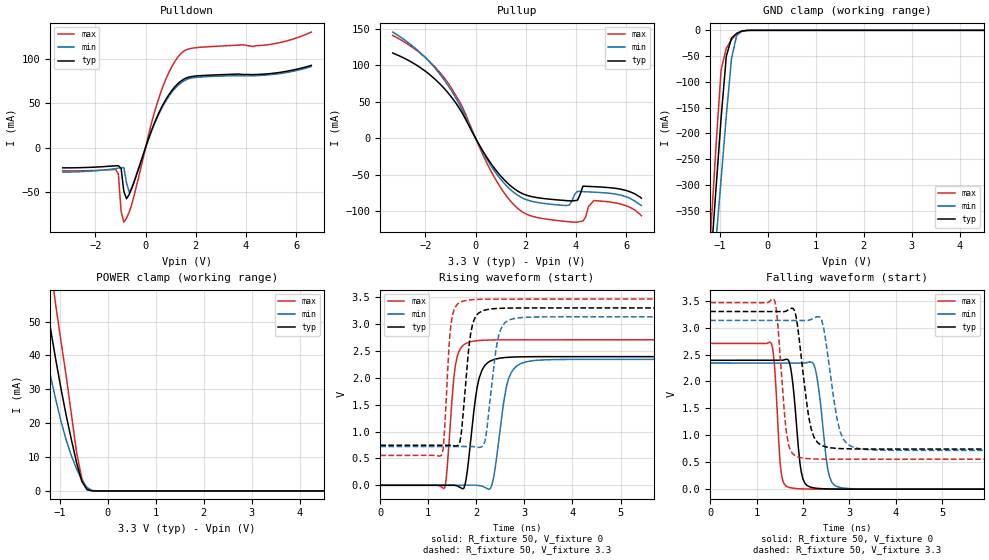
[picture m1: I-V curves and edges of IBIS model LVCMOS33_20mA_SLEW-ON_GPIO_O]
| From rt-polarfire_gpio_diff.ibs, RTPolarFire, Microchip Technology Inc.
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|   Model LVCMOS33_20mA_SLEW-ON_GPIO_O
[Model]   LVCMOS33_20mA_SLEW-ON_GPIO_O
Model_type   Output
Polarity   Non-Inverting
Enable   Active-High
Vmeas =   1.65
Cref =   5p
Rref =   1M
|   typ   min   max
C_comp_pullup   2.605e-12   2.605e-12   2.76e-12
C_comp_pulldown  2.605e-12   2.605e-12   2.76e-12
[Temperature Range]  25C   125C   -55C
[Voltage Range]  3.3   3.135   3.465
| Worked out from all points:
|   slope of the pulldown table from 0 to 0.495 V, typ, clamps not added: 13.4 ohm
|   slope of the pullup table from 0 to 0.495 V, typ, clamps not added: 17.3 ohm
|   GND clamp passes 1 mA (typ) near -0.51 V on its own axis
|   POWER clamp passes 1 mA (typ) near -0.46 V on its own axis
|   rising waveform, R_fixture 50, V_fixture 0: 20-80 % time 199ps typ, 224ps min, 143ps max; typ from 0 V to 2.39 V
|   rising waveform, R_fixture 50, V_fixture 3.3: 20-80 % time 160ps typ, 194ps min, 115ps max; typ from 0.745 V to 3.3 V
|   falling waveform, R_fixture 50, V_fixture 0: 20-80 % time 149ps typ, 181ps min, 107ps max; typ from 2.39 V to 0 V
|   falling waveform, R_fixture 50, V_fixture 3.3: 20-80 % time 226ps typ, 254ps min, 158ps max; typ from 3.3 V to 0.745 V
[GND Clamp]
| Voltage   I(typ)   I(min)   I(max)
-3.3V     -3.213A    -2.953A    -3.676A
-1.191V   -450mA     -534.3mA   -393.2mA
-1.083V   -310.2mA   -411.6mA   -227.5mA
-974.5mV  -170.4mA   -288.9mA   -76.97mA
-866.2mV  -50.48mA   -166.3mA   -34.78mA
-758mV    -15.08mA   -54.7mA    -18.33mA
-649.7mV  -5.883mA   -9.683mA   -6.874mA
-541.4mV  -1.389mA   -1.864mA   -1.426mA
-324.8mV  -3.553uA   -16.68uA   -1.172uA
6.6V      0A         0A         0A
[POWER Clamp]
| Voltage   I(typ)   I(min)   I(max)
-3.3V     320.3mA    256.6mA    387.1mA
-1.624V   89.11mA    65.97mA    116.9mA
-1.408V   67.23mA    48.87mA    90.32mA
-1.299V   57.08mA    41.04mA    77.84mA
-1.191V   47.51mA    33.68mA    65.79mA
-1.083V   38.51mA    26.79mA    54.52mA
-866.2mV  22.14mA    14.9mA     33.75mA
-649.7mV  8.213mA    6.429mA    11.19mA
-541.4mV  2.791mA    3.18mA     3.642mA
-433.1mV  359.8uA    981.3uA    499.4uA
-216.6mV  159.8nA    8.88uA     59.07nA
6.6V      0A         0A         0A
[Pullup]
| Voltage   I(typ)   I(min)   I(max)
-3.3V     117mA      145.7mA    141.1mA
-2.057V   93.5mA     112.8mA    112.5mA
-1.191V   66.14mA    77.19mA    80.37mA
-541.4mV  35.17mA    39.57mA    43.91mA
618.8mV   -34.87mA   -38.07mA   -45.43mA
1.753V    -73.94mA   -79.81mA   -98.31mA
3.625V    -85.57mA   -92.33mA   -114.2mA
4.058V    -84.98mA   -72.83mA   -114.9mA
4.275V    -65.71mA   -73.19mA   -113.6mA
4.708V    -66.38mA   -73.95mA   -85.52mA
5.79V     -69.97mA   -78.11mA   -90.3mA
6.6V      -82.26mA   -92.3mA    -106.2mA
[Pulldown]
| Voltage   I(typ)   I(min)   I(max)
-3.3V     -22.95mA   -27.7mA    -26.21mA
-1.191V   -20.65mA   -23.8mA    -24.73mA
-1.083V   -20.45mA   -23.29mA   -29.63mA
-974.5mV  -23.56mA   -22.74mA   -72.15mA
-866.2mV  -49.58mA   -22.71mA   -84.24mA
-758mV    -57.79mA   -39.9mA    -79.68mA
-649.7mV  -52.66mA   -50.34mA   -72.76mA
515.6mV   38.32mA    37.03mA    54.75mA
928.1mV   59.63mA    57.85mA    84.81mA
1.444V    75.7mA     73.69mA    107mA
4.924V    83.32mA    82.08mA    116.2mA
6.6V      92.71mA    91.43mA    130.3mA
[Ramp]
dV/dt_r   1.43641/0.199051n  1.40571/0.224051n  1.62438/0.143217n
dV/dt_f   1.53328/0.226109n  1.44881/0.253893n  1.74553/0.158052n
R_load = 50
[Rising Waveform]
R_fixture = 50
V_fixture = 0
V_fixture_min = 0
V_fixture_max = 0
| Time   V(typ)   V(min)   V(max)
0s        32.7nV     45.65nV    84.14nV
1.332ns   814.5uV    553.9uV    -55.06mV
1.563ns   -3.648mV   649.9uV    2.226V
1.741ns   -50.85mV   724uV      2.616V
1.863ns   674.6mV    774.7uV    2.668V
2.115ns   2.141V     -16.32mV   2.698V
2.324ns   2.326V     9.939mV    2.704V
2.666ns   2.381V     1.972V     2.707V
3.008ns   2.391V     2.291V     2.707V
10ns      2.394V     2.343V     2.707V
[Rising Waveform]
R_fixture = 50
V_fixture = 3.3
V_fixture_min = 3.135
V_fixture_max = 3.465
| Time   V(typ)   V(min)   V(max)
0s        744.5mV    720.3mV    555.8mV
1.283ns   745.3mV    721mV      574.7mV
1.468ns   745.2mV    721.1mV    2.966V
1.642ns   771mV      721.2mV    3.394V
1.717ns   1.259V     721.2mV    3.425V
1.944ns   3.059V     719.5mV    3.455V
2.182ns   3.261V     830.6mV    3.463V
2.439ns   3.29V      2.684V     3.464V
2.695ns   3.297V     3.08V      3.464V
10ns      3.3V       3.135V     3.465V
[Falling Waveform]
R_fixture = 50
V_fixture = 0
V_fixture_min = 0
V_fixture_max = 0
| Time   V(typ)   V(min)   V(max)
0s        2.394V     2.343V     2.707V
1.307ns   2.395V     2.342V     2.718V
1.528ns   2.395V     2.342V     315.6mV
1.706ns   2.349V     2.342V     30.97mV
1.961ns   321.5mV    2.342V     6.279mV
2.146ns   41.12mV    2.362V     2.346mV
2.301ns   15.93mV    2.072V     934.8uV
2.533ns   4.76mV     370.7mV    322.3uV
2.732ns   1.761mV    47.32mV    270.7uV
10ns      29.94nV    3.479uV    394.6nV
[Falling Waveform]
R_fixture = 50
V_fixture = 3.3
V_fixture_min = 3.135
V_fixture_max = 3.465
| Time   V(typ)   V(min)   V(max)
0s        3.3V       3.135V     3.465V
1.374ns   3.299V     3.135V     3.523V
1.637ns   3.308V     3.134V     1.081V
1.808ns   3.329V     3.134V     633.8mV
1.913ns   2.816V     3.134V     591.6mV
2.238ns   962.3mV    3.183V     561mV
2.446ns   799.2mV    2.989V     557.5mV
2.8ns     753.2mV    1.065V     556.2mV
3.128ns   746.6mV    767.6mV    556.2mV
10ns      744.5mV    720.3mV    555.8mV
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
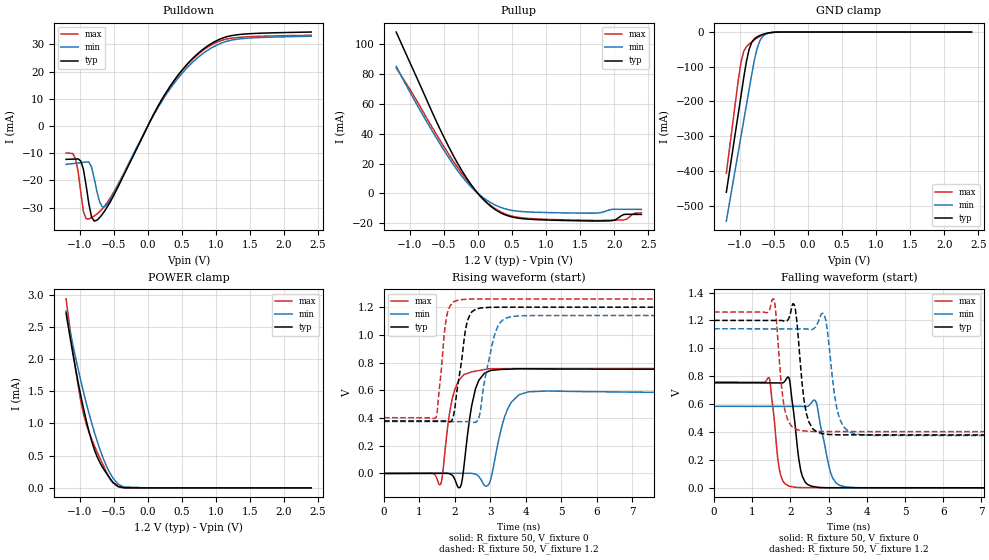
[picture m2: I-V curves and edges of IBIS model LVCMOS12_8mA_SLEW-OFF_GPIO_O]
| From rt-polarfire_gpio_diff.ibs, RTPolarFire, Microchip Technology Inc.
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|   Model LVCMOS12_8mA_SLEW-OFF_GPIO_O
[Model]   LVCMOS12_8mA_SLEW-OFF_GPIO_O
Model_type   Output
Polarity   Non-Inverting
Enable   Active-High
Vmeas =   0.6
Cref =   5p
Rref =   1M
|   typ   min   max
C_comp_pullup   2.605e-12   2.605e-12   2.76e-12
C_comp_pulldown  2.605e-12   2.605e-12   2.76e-12
[Temperature Range]  25C   125C   -55C
[Voltage Range]  1.2   1.14   1.26
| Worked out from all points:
|   slope of the pulldown table from 0 to 0.18 V, typ, clamps not added: 21 ohm
|   slope of the pullup table from 0 to 0.18 V, typ, clamps not added: 21.8 ohm
|   GND clamp passes 1 mA (typ) near -0.52 V on its own axis
|   POWER clamp passes 1 mA (typ) near -0.89 V on its own axis
|   rising waveform, R_fixture 50, V_fixture 0: 20-80 % time 274ps typ, 353ps min, 280ps max; typ from 0 V to 0.753 V
|   rising waveform, R_fixture 50, V_fixture 1.2: 20-80 % time 267ps typ, 346ps min, 193ps max; typ from 0.379 V to 1.2 V
|   falling waveform, R_fixture 50, V_fixture 0: 20-80 % time 198ps typ, 270ps min, 172ps max; typ from 0.753 V to 0 V
|   falling waveform, R_fixture 50, V_fixture 1.2: 20-80 % time 193ps typ, 231ps min, 180ps max; typ from 1.2 V to 0.379 V
[GND Clamp]
| Voltage   I(typ)   I(min)   I(max)
-1.2V     -461.6mA   -544.4mA   -406.8mA
-1.024V   -233.9mA   -344.7mA   -137.6mA
-984.4mV  -183.1mA   -300.1mA   -86.85mA
-945mV    -132.4mA   -255.5mA   -55.69mA
-905.6mV  -85.65mA   -210.9mA   -42.32mA
-866.2mV  -50.48mA   -166.3mA   -34.78mA
-826.9mV  -29.63mA   -121.9mA   -28.32mA
-748.1mV  -13.93mA   -47.49mA   -17.05mA
-708.7mV  -10.12mA   -25.53mA   -12.4mA
-630mV    -4.768mA   -7.139mA   -5.445mA
-354.4mV  -10.06uA   -36.07uA   -4.668uA
2.4V      0A         0A         0A
[POWER Clamp]
| Voltage   I(typ)   I(min)   I(max)
-1.2V     2.715mA    2.748mA    2.936mA
-1.063V   1.865mA    2.037mA    1.863mA
-984.4mV  1.435mA    1.667mA    1.351mA
-945mV    1.238mA    1.493mA    1.151mA
-905.6mV  1.055mA    1.327mA    995uA
-826.9mV  734.5uA    1.017mA    763.7uA
-748.1mV  493.1uA    740.4uA    565.4uA
-630mV    262.2uA    394.7uA    295.2uA
-511.9mV  86.82uA    151.1uA    75.54uA
-433.1mV  20.57uA    56.17uA    14.03uA
-315mV    557nA      11.55uA    355.3nA
2.4V      0A         0A         0A
[Pullup]
| Voltage   I(typ)   I(min)   I(max)
-1.2V     108mA      85.07mA    84.01mA
-787.5mV  66.26mA    50.8mA     53.28mA
-354.4mV  24.78mA    18.92mA    21.18mA
-39.38mV  2.212mA    1.618mA    2.065mA
225mV     -9.85mA    -7.069mA   -9.29mA
525mV     -15.97mA   -11.49mA   -15.39mA
975mV     -17.7mA    -12.72mA   -17.25mA
1.751V    -18.42mA   -13.09mA   -18.03mA
1.948V    -18.26mA   -10.76mA   -17.9mA
2.145V    -14.03mA   -10.57mA   -17.68mA
2.303V    -13.99mA   -10.62mA   -13.18mA
2.4V      -14.02mA   -10.65mA   -12.99mA
[Pulldown]
| Voltage   I(typ)   I(min)   I(max)
-1.2V     -12.28mA   -14.1mA    -9.949mA
-1.063V   -12.15mA   -13.73mA   -11.99mA
-984.4mV  -12.87mA   -13.49mA   -24.29mA
-905.6mV  -21.86mA   -13.23mA   -34.14mA
-826.9mV  -33.38mA   -15.07mA   -33.72mA
-748.1mV  -34.68mA   -23.94mA   -32.39mA
-669.4mV  -32.52mA   -29.71mA   -30.5mA
-590.6mV  -29.58mA   -28.68mA   -27.97mA
225mV     10.49mA    9.836mA    10.48mA
750mV     26.97mA    25.48mA    26.6mA
1.239V    33.27mA    31.64mA    32.33mA
2.4V      34.55mA    33.01mA    33.36mA
[Ramp]
dV/dt_r   0.451605/0.273754n  0.350623/0.353382n  0.454656/0.280114n
dV/dt_f   0.492719/0.192735n  0.45915/0.23053n  0.514553/0.179576n
R_load = 50
[Rising Waveform]
R_fixture = 50
V_fixture = 0
V_fixture_min = 0
V_fixture_max = 0
| Time   V(typ)   V(min)   V(max)
0s        9.965nV    27.28nV    13.23nV
1.585ns   913.9uV    667.6uV    -81.24mV
1.924ns   -13.16mV   810.4uV    539.7mV
2.145ns   -100.9mV   903.5uV    682.3mV
2.492ns   511.8mV    -171uV     734.7mV
2.672ns   671.9mV    -22.15mV   742.6mV
2.971ns   739.2mV    -70.39mV   755.6mV
3.482ns   752.2mV    464.1mV    756.4mV
4.072ns   754.8mV    589.1mV    757.1mV
10ns      752.7mV    584.4mV    757.8mV
[Rising Waveform]
R_fixture = 50
V_fixture = 1.2
V_fixture_min = 1.14
V_fixture_max = 1.26
| Time   V(typ)   V(min)   V(max)
0s        378.8mV    374.7mV    402.4mV
1.463ns   378.5mV    374.4mV    403.4mV
1.766ns   376.6mV    374.4mV    1.132V
1.937ns   395.5mV    374.3mV    1.231V
2.059ns   599mV      374.3mV    1.249V
2.431ns   1.151V     371.4mV    1.258V
2.667ns   1.191V     396mV      1.259V
3.096ns   1.199V     982.1mV    1.259V
3.43ns    1.2V       1.12V      1.259V
10ns      1.2V       1.14V      1.26V
[Falling Waveform]
R_fixture = 50
V_fixture = 0
V_fixture_min = 0
V_fixture_max = 0
| Time   V(typ)   V(min)   V(max)
0s        752.7mV    584.2mV    757.8mV
1.442ns   752mV      583.7mV    788.1mV
1.706ns   751.9mV    583.6mV    135.8mV
1.965ns   783.9mV    583.5mV    11.73mV
2.267ns   126mV      583.4mV    1.845mV
2.555ns   10.85mV    612.5mV    414.6uV
2.682ns   5.56mV     605.4mV    407.5uV
3.051ns   770.5uV    107.9mV    386.9uV
3.405ns   731.2uV    8.48mV     367.2uV
10ns      -1.393uV   -20.77uV   -465.8nV
[Falling Waveform]
R_fixture = 50
V_fixture = 1.2
V_fixture_min = 1.14
V_fixture_max = 1.26
| Time   V(typ)   V(min)   V(max)
0s        1.2V       1.14V      1.26V
1.561ns   1.2V       1.14V      1.353V
1.855ns   1.193V     1.139V     554.1mV
2.19ns    1.122V     1.139V     414.9mV
2.417ns   531.4mV    1.139V     406.8mV
2.692ns   400.7mV    1.169V     403.9mV
2.887ns   386.3mV    1.24V      403.4mV
3.215ns   380.2mV    566.3mV    403.1mV
3.53ns    379.5mV    402mV      403.1mV
10ns      378.8mV    374.8mV    402.4mV
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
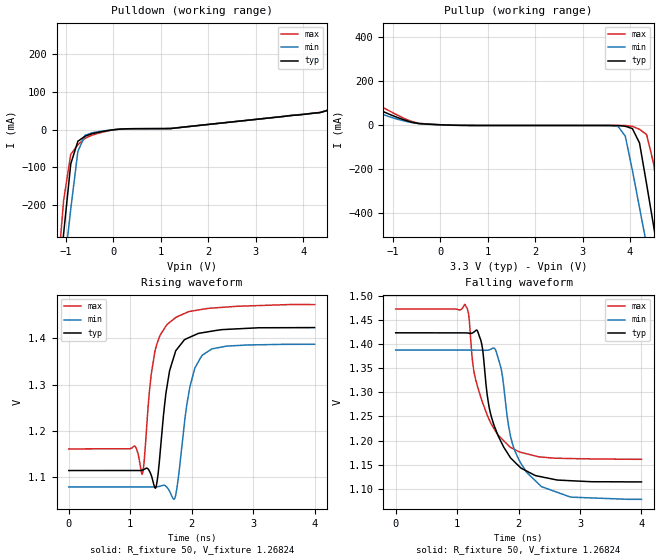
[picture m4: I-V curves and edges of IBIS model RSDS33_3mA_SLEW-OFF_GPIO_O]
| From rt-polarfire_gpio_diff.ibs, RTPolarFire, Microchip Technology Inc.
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|   Model RSDS33_3mA_SLEW-OFF_GPIO_O
[Model]   RSDS33_3mA_SLEW-OFF_GPIO_O
Model_type   Output
Polarity   Non-Inverting
Enable   Active-High
Vmeas =   1.2
Cref =   5p
Rref =   100
|   typ   min   max
C_comp_pullup   2.605e-12   2.605e-12   2.76e-12
C_comp_pulldown  2.605e-12   2.605e-12   2.76e-12
[Temperature Range]  25C   125C   -55C
[Voltage Range]  3.3   3.15   3.45
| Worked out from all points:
|   slope of the pulldown table from 0 to 0.495 V, typ, clamps not added: 175 ohm
|   slope of the pullup table from 0 to 0.495 V, typ, clamps not added: 176 ohm
|   rising waveform, R_fixture 50, V_fixture 1.26824: 20-80 % time 211ps typ, 212ps min, 229ps max; typ from 1.11 V to 1.42 V
|   falling waveform, R_fixture 50, V_fixture 1.26824: 20-80 % time 372ps typ, 356ps min, 386ps max; typ from 1.42 V to 1.11 V
[Pulldown]
|Voltage   I(typ)   I(min)   I(max)
-3.3V     -3.224A    -2.962A    -3.688A
-1.2V     -469mA     -550.4mA   -416.2mA
-1.05V    -275mA     -380.2mA   -186.6mA
-900mV    -90.55mA   -210.1mA   -65.04mA
-750mV    -30.57mA   -57.34mA   -39.87mA
-600mV    -17.3mA    -14.85mA   -22.87mA
150mV     1.774mA    1.437mA    2.148mA
4.5V      50.71mA    50.63mA    51.19mA
5.1V      117.6mA    106.7mA    124.6mA
6V        247.2mA    218.4mA    274.7mA
6.15V     271.7mA    239.6mA    302.1mA
6.6V      350.8mA    306.2mA    389mA
[Pullup]
|Voltage   I(typ)   I(min)   I(max)
-3.3V     375.6mA    307.1mA    445.3mA
-1.8V     130.3mA    102.8mA    162.1mA
-600mV    11.44mA    9.761mA    14.9mA
3.75V     -3.395mA   -7.815mA   -3.224mA
3.9V      -6.612mA   -51.83mA   -3.417mA
4.05V     -17.46mA   -207.3mA   -6.99mA
4.2V      -82.7mA    -377.2mA   -20.67mA
4.35V     -270.5mA   -547.2mA   -44.38mA
4.5V      -464.3mA   -717mA     -179.9mA
4.65V     -658.2mA   -887.1mA   -409.4mA
4.8V      -852.4mA   -1.057A    -639mA
6.6V      -3.216A    -3.129A    -3.441A
[Ramp]
| variable   typ   min   max
dV/dt_r 0.2082/0.2132e-9   0.2010/0.2193e-9   0.2197/0.2140e-9
dV/dt_f 0.1885/0.3697e-9   0.1877/0.3550e-9   0.1924/0.3811e-9
R_load = 50
[Rising waveform]
R_fixture= 50
V_fixture= 1.26824
V_fixture_min= 1.23302
V_fixture_max= 1.31582
|Time   V(typ)   V(min)   V(max)
0s        1.114V     1.079V     1.161V
1.07ns    1.114V     1.079V     1.167V
1.19ns    1.115V     1.079V     1.106V
1.33ns    1.108V     1.079V     1.309V
1.42ns    1.079V     1.079V     1.381V
1.58ns    1.281V     1.081V     1.426V
1.71ns    1.36V      1.052V     1.442V
1.96ns    1.402V     1.288V     1.458V
2.17ns    1.412V     1.363V     1.462V
4ns       1.423V     1.387V     1.472V
[Falling waveform]
R_fixture= 50
V_fixture= 1.26824
V_fixture_min= 1.23302
V_fixture_max= 1.31582
|Time   V(typ)   V(min)   V(max)
0s        1.423V     1.387V     1.472V
1.13ns    1.423V     1.387V     1.481V
1.19ns    1.422V     1.387V     1.458V
1.25ns    1.423V     1.387V     1.365V
1.32ns    1.429V     1.387V     1.317V
1.63ns    1.222V     1.386V     1.218V
1.73ns    1.194V     1.339V     1.203V
1.87ns    1.164V     1.208V     1.186V
2.37ns    1.125V     1.105V     1.166V
4ns       1.115V     1.079V     1.161V
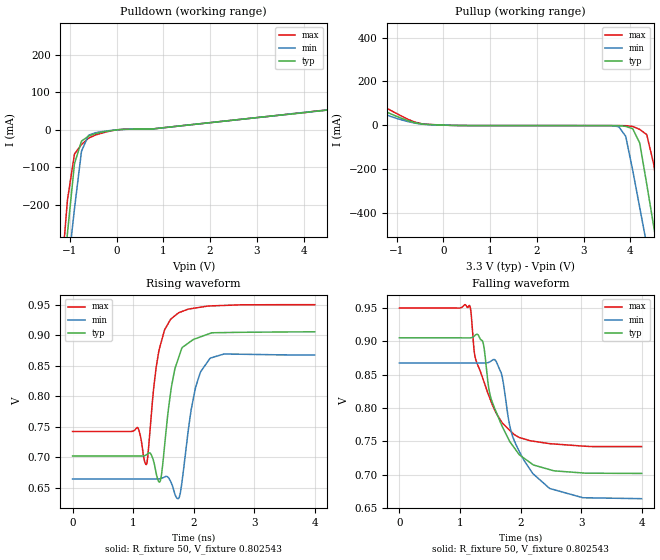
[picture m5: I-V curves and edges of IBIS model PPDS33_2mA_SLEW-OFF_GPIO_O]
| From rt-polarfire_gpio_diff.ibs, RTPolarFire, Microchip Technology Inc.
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|   Model PPDS33_2mA_SLEW-OFF_GPIO_O
[Model]   PPDS33_2mA_SLEW-OFF_GPIO_O
Model_type   Output
Polarity   Non-Inverting
Enable   Active-High
Vmeas =   0.8
Cref =   5p
Rref =   100
|   typ   min   max
C_comp_pullup   2.605e-12   2.605e-12   2.76e-12
C_comp_pulldown  2.605e-12   2.605e-12   2.76e-12
[Temperature Range]  25C   125C   -55C
[Voltage Range]  3.3   3.15   3.45
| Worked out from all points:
|   slope of the pulldown table from 0 to 0.495 V, typ, clamps not added: 256 ohm
|   slope of the pullup table from 0 to 0.495 V, typ, clamps not added: 256 ohm
|   rising waveform, R_fixture 50, V_fixture 0.802543: 20-80 % time 213ps typ, 209ps min, 207ps max; typ from 0.702 V to 0.906 V
|   falling waveform, R_fixture 50, V_fixture 0.802543: 20-80 % time 448ps typ, 446ps min, 445ps max; typ from 0.906 V to 0.702 V
[Pulldown]
|Voltage   I(typ)   I(min)   I(max)
-3.3V     -3.224A    -2.962A    -3.688A
-1.2V     -468.8mA   -550.2mA   -415.8mA
-1.05V    -274.8mA   -380mA     -186.2mA
-900mV    -90.11mA   -209.8mA   -64.26mA
-750mV    -30mA      -57mA      -39.13mA
-600mV    -16.77mA   -14.45mA   -22.19mA
0V        -41.41uA   -36.01uA   -50.7uA
4.5V      52.76mA    52.71mA    52.31mA
5.1V      116.8mA    105.8mA    123.8mA
6V        246.3mA    217.5mA    273.8mA
6.15V     270.7mA    238.7mA    301.1mA
6.6V      349.9mA    305.3mA    388mA
[Pullup]
|Voltage   I(typ)   I(min)   I(max)
-3.3V     376.6mA    307.7mA    446.3mA
-1.65V    109.6mA    86.74mA    137.1mA
-600mV    10.25mA    8.871mA    13.4mA
3.75V     -2.332mA   -6.734mA   -2.149mA
3.9V      -5.526mA   -50.81mA   -2.339mA
4.05V     -16.34mA   -206.4mA   -5.89mA
4.2V      -81.69mA   -376.3mA   -19.52mA
4.35V     -269.6mA   -546.2mA   -43.19mA
4.5V      -463.3mA   -716.1mA   -179mA
4.65V     -657.3mA   -886.1mA   -408.4mA
4.8V      -851.4mA   -1.056A    -637.8mA
6.6V      -3.215A    -3.128A    -3.44A
[Ramp]
| variable   typ   min   max
dV/dt_r 0.1480/0.2178e-9   0.1425/0.2218e-9   0.1578/0.2127e-9
dV/dt_f 0.1254/0.4443e-9   0.1253/0.4454e-9   0.1279/0.4407e-9
R_load = 50
[Rising waveform]
R_fixture= 50
V_fixture= 0.802543
V_fixture_min= 0.765098
V_fixture_max= 0.846243
|Time   V(typ)   V(min)   V(max)
0s        701.8mV    664.1mV    742.2mV
1.07ns    701.8mV    664.1mV    748.7mV
1.22ns    703.9mV    664.1mV    687.8mV
1.34ns    693mV      664.1mV    813.3mV
1.45ns    661.3mV    664.7mV    883.8mV
1.63ns    813.8mV    658.1mV    927.2mV
1.75ns    862.9mV    632.3mV    936.9mV
2.03ns    894.4mV    813.8mV    944.8mV
2.27ns    903.1mV    862.2mV    948.1mV
4ns       905.7mV    867.7mV    950.2mV
[Falling waveform]
R_fixture= 50
V_fixture= 0.802543
V_fixture_min= 0.765098
V_fixture_max= 0.846243
|Time   V(typ)   V(min)   V(max)
0s        905.6mV    867.8mV    950.3mV
1.16ns    905.3mV    867.8mV    953.9mV
1.25ns    909.2mV    867.8mV    876.5mV
1.38ns    898.8mV    867.6mV    843.8mV
1.48ns    827.1mV    868.9mV    817.9mV
1.6ns     793.7mV    869.8mV    792.3mV
1.69ns    773.9mV    849.9mV    779.2mV
1.9ns     740.1mV    750.3mV    760mV
2.48ns    707.8mV    679.6mV    746.8mV
4ns       702.1mV    664.2mV    742.3mV
